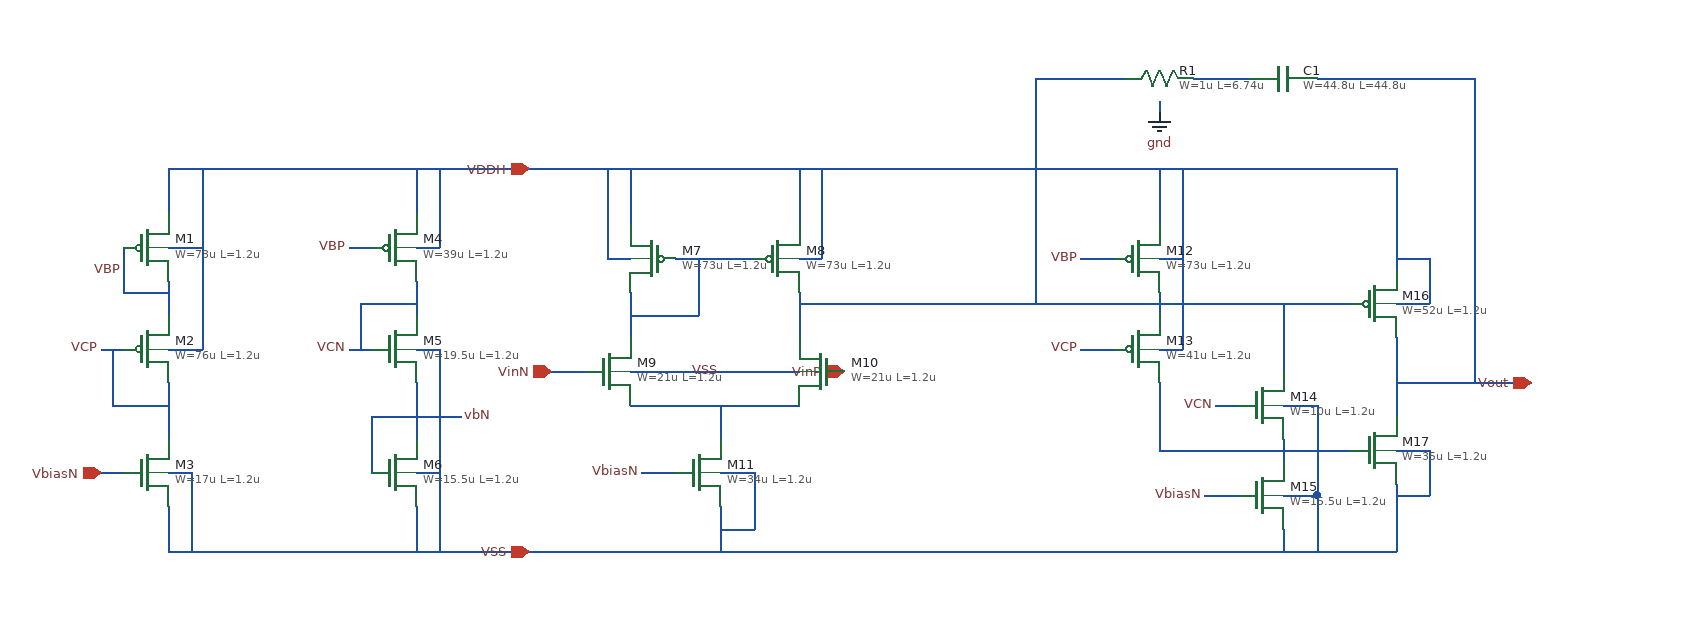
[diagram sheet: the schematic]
v {xschem version=3.4.8RC file_version=1.3}
G {}
K {}
V {}
S {}
F {}
E {}
N -3610 -1060 -3610 -1030 {lab=VBP}
N -3610 -970 -3610 -920 {lab=VCP}
N -3650 -1090 -3650 -1050 {lab=VBP}
N -3650 -1050 -3610 -1050 {lab=VBP}
N -3670 -1000 -3650 -1000 {lab=VCP}
N -3660 -1000 -3660 -950 {lab=VCP}
N -3660 -950 -3610 -950 {lab=VCP}
N -3610 -860 -3610 -820 {lab=VSS}
N -3610 -820 -2930 -820 {lab=VSS}
N -3610 -890 -3590 -890 {lab=VSS}
N -3590 -890 -3590 -820 {lab=VSS}
N -3670 -890 -3650 -890 {lab=VbiasN}
N -3610 -1000 -3580 -1000 {lab=VDDH}
N -3580 -1160 -3580 -1000 {lab=VDDH}
N -3610 -1090 -3580 -1090 {lab=VDDH}
N -3610 -1160 -3610 -1120 {lab=VDDH}
N -3610 -1160 -2940 -1160 {lab=VDDH}
N -3390 -1160 -3390 -1120 {lab=VDDH}
N -3390 -1090 -3370 -1090 {lab=VDDH}
N -3370 -1160 -3370 -1090 {lab=VDDH}
N -3450 -1090 -3430 -1090 {lab=VBP}
N -3390 -1060 -3390 -1030 {lab=VCN}
N -3390 -970 -3390 -920 {lab=vbN}
N -3390 -860 -3390 -820 {lab=VSS}
N -3390 -890 -3370 -890 {lab=VSS}
N -3370 -890 -3370 -820 {lab=VSS}
N -3390 -1000 -3370 -1000 {lab=VSS}
N -3370 -1000 -3370 -880 {lab=VSS}
N -3450 -1000 -3430 -1000 {lab=VCN}
N -3440 -1040 -3440 -1000 {lab=VCN}
N -3440 -1040 -3390 -1040 {lab=VCN}
N -3430 -940 -3430 -890 {lab=vbN}
N -3430 -940 -3390 -940 {lab=vbN}
N -3390 -940 -3350 -940 {lab=vbN}
N -3200 -1160 -3200 -1110 {lab=VDDH}
N -3220 -1080 -3200 -1080 {lab=VDDH}
N -3220 -1160 -3220 -1080 {lab=VDDH}
N -3200 -1050 -3200 -1010 {lab=#net1}
N -3200 -1030 -3200 -1010 {lab=#net1}
N -3200 -1030 -3140 -1030 {lab=#net1}
N -3140 -1080 -3140 -1030 {lab=#net1}
N -3200 -950 -3050 -950 {lab=#net2}
N -3120 -950 -3120 -920 {lab=#net2}
N -3200 -980 -3050 -980 {lab=VSS}
N -3270 -980 -3240 -980 {lab=VinN}
N -3120 -890 -3090 -890 {lab=VSS}
N -3090 -890 -3090 -840 {lab=VSS}
N -3120 -840 -3090 -840 {lab=VSS}
N -3120 -860 -3120 -820 {lab=VSS}
N -3190 -890 -3160 -890 {lab=VbiasN}
N -2800 -1080 -2770 -1080 {lab=VBP}
N -2800 -1000 -2770 -1000 {lab=VCP}
N -2730 -1050 -2730 -1030 {lab=#net3}
N -2940 -1160 -2530 -1160 {lab=VDDH}
N -2730 -1160 -2730 -1110 {lab=VDDH}
N -2730 -1080 -2710 -1080 {lab=VDDH}
N -2710 -1160 -2710 -1080 {lab=VDDH}
N -2730 -1000 -2710 -1000 {lab=VDDH}
N -2710 -1100 -2710 -1000 {lab=VDDH}
N -2620 -920 -2620 -900 {lab=#net4}
N -2690 -870 -2660 -870 {lab=VbiasN}
N -2620 -840 -2620 -820 {lab=VSS}
N -2620 -870 -2590 -870 {lab=VSS}
N -2590 -870 -2590 -820 {lab=VSS}
N -2620 -950 -2590 -950 {lab=VSS}
N -2590 -950 -2590 -870 {lab=VSS}
N -2680 -950 -2660 -950 {lab=VCN}
N -2620 -1040 -2620 -980 {lab=#net3}
N -2730 -1040 -2560 -1040 {lab=#net3}
N -2520 -1010 -2520 -940 {lab=Vout}
N -2620 -910 -2560 -910 {lab=#net4}
N -2520 -880 -2520 -820 {lab=VSS}
N -2940 -820 -2520 -820 {lab=VSS}
N -2520 -910 -2490 -910 {lab=VSS}
N -2490 -910 -2490 -870 {lab=VSS}
N -2520 -870 -2490 -870 {lab=VSS}
N -2520 -1160 -2520 -1070 {lab=VDDH}
N -2530 -1160 -2520 -1160 {lab=VDDH}
N -2520 -1040 -2490 -1040 {lab=VDDH}
N -2490 -1080 -2490 -1040 {lab=VDDH}
N -2520 -1080 -2490 -1080 {lab=VDDH}
N -2520 -970 -2400 -970 {lab=Vout}
N -3050 -1160 -3050 -1110 {lab=VDDH}
N -3160 -1080 -3090 -1080 {lab=#net1}
N -3050 -1050 -3050 -1010 {lab=#net3}
N -2850 -1040 -2730 -1040 {lab=#net3}
N -3050 -1040 -2830 -1040 {lab=#net3}
N -2840 -1240 -2840 -1070 {lab=#net3}
N -2840 -1240 -2760 -1240 {lab=#net3}
N -2840 -1070 -2840 -1040 {lab=#net3}
N -2730 -1220 -2730 -1210 {lab=gnd}
N -2700 -1240 -2650 -1240 {lab=#net5}
N -2590 -1240 -2450 -1240 {lab=Vout}
N -2450 -1240 -2450 -970 {lab=Vout}
N -3050 -1080 -3030 -1080 {lab=VDDH}
N -3030 -1160 -3030 -1080 {lab=VDDH}
N -2730 -970 -2730 -910 {lab=#net4}
N -2730 -910 -2620 -910 {lab=#net4}
C {symbols/ppolyf_u.sym} -2730 -1240 3 0 {name=R1
W=1u
L=6.74u
model=ppolyf_u
spiceprefix=X
m=1}
C {symbols/cap_mim_2f0fF.sym} -2620 -1240 3 0 {name=C1
W=44.8u
L=44.8u
model=cap_mim_2f0fF
spiceprefix=X
m=1}
C {gnd.sym} -2730 -1210 0 0 {name=l1 lab=gnd}
C {ipin.sym} -3670 -890 0 0 {name=p1 lab=VbiasN}
C {ipin.sym} -3290 -820 3 0 {name=p2 lab=VSS}
C {ipin.sym} -3290 -1160 1 0 {name=p3 lab=VDDH}
C {ipin.sym} -3270 -980 0 0 {name=p4 lab=VinN}
C {ipin.sym} -3010 -980 2 0 {name=p5 lab=VinP}
C {ipin.sym} -2400 -970 2 0 {name=p6 lab=Vout}
C {lab_pin.sym} -3450 -1090 0 0 {name=p7 sig_type=std_logic lab=VBP}
C {lab_pin.sym} -3450 -1000 0 0 {name=p8 sig_type=std_logic lab=VCN}
C {lab_pin.sym} -3350 -940 2 0 {name=p9 sig_type=std_logic lab=vbN}
C {lab_pin.sym} -3670 -1000 0 0 {name=p10 sig_type=std_logic lab=VCP}
C {lab_pin.sym} -3650 -1070 0 0 {name=p11 sig_type=std_logic lab=VBP}
C {lab_pin.sym} -3190 -890 0 0 {name=p12 sig_type=std_logic lab=VbiasN}
C {lab_pin.sym} -2690 -870 0 0 {name=p13 sig_type=std_logic lab=VbiasN}
C {lab_pin.sym} -2680 -950 0 0 {name=p14 sig_type=std_logic lab=VCN}
C {lab_pin.sym} -2800 -1000 0 0 {name=p15 sig_type=std_logic lab=VCP}
C {lab_pin.sym} -2800 -1080 0 0 {name=p16 sig_type=std_logic lab=VBP}
C {lab_pin.sym} -3120 -980 0 0 {name=p17 sig_type=std_logic lab=VSS}
C {symbols/nfet_03v3.sym} -3140 -890 0 0 {name=M11
L=1.2u
W=34u
nf=8
m=1
ad="'int((nf+1)/2) * W/nf * 0.18u'"
pd="'2*int((nf+1)/2) * (W/nf + 0.18u)'"
as="'int((nf+2)/2) * W/nf * 0.18u'"
ps="'2*int((nf+2)/2) * (W/nf + 0.18u)'"
nrd="'0.18u / W'" nrs="'0.18u / W'"
sa=0 sb=0 sd=0
model=nfet_03v3
spiceprefix=X
}
C {symbols/pfet_03v3.sym} -3180 -1080 0 1 {name=M7
L=1.2u
W=73u
nf=16
m=1
ad="'int((nf+1)/2) * W/nf * 0.18u'"
pd="'2*int((nf+1)/2) * (W/nf + 0.18u)'"
as="'int((nf+2)/2) * W/nf * 0.18u'"
ps="'2*int((nf+2)/2) * (W/nf + 0.18u)'"
nrd="'0.18u / W'" nrs="'0.18u / W'"
sa=0 sb=0 sd=0
model=pfet_03v3
spiceprefix=X
}
C {symbols/pfet_03v3.sym} -3070 -1080 0 0 {name=M8
L=1.2u
W=73u
nf=16
m=1
ad="'int((nf+1)/2) * W/nf * 0.18u'"
pd="'2*int((nf+1)/2) * (W/nf + 0.18u)'"
as="'int((nf+2)/2) * W/nf * 0.18u'"
ps="'2*int((nf+2)/2) * (W/nf + 0.18u)'"
nrd="'0.18u / W'" nrs="'0.18u / W'"
sa=0 sb=0 sd=0
model=pfet_03v3
spiceprefix=X
}
C {symbols/nfet_03v3.sym} -3220 -980 0 0 {name=M9
L=1.2u
W=21u
nf=5
m=1
ad="'int((nf+1)/2) * W/nf * 0.18u'"
pd="'2*int((nf+1)/2) * (W/nf + 0.18u)'"
as="'int((nf+2)/2) * W/nf * 0.18u'"
ps="'2*int((nf+2)/2) * (W/nf + 0.18u)'"
nrd="'0.18u / W'" nrs="'0.18u / W'"
sa=0 sb=0 sd=0
model=nfet_03v3
spiceprefix=X
}
C {symbols/nfet_03v3.sym} -3030 -980 0 1 {name=M10
L=1.2u
W=21u
nf=5
m=1
ad="'int((nf+1)/2) * W/nf * 0.18u'"
pd="'2*int((nf+1)/2) * (W/nf + 0.18u)'"
as="'int((nf+2)/2) * W/nf * 0.18u'"
ps="'2*int((nf+2)/2) * (W/nf + 0.18u)'"
nrd="'0.18u / W'" nrs="'0.18u / W'"
sa=0 sb=0 sd=0
model=nfet_03v3
spiceprefix=X
}
C {symbols/pfet_03v3.sym} -2750 -1080 0 0 {name=M12
L=1.2u
W=73u
nf=16
m=1
ad="'int((nf+1)/2) * W/nf * 0.18u'"
pd="'2*int((nf+1)/2) * (W/nf + 0.18u)'"
as="'int((nf+2)/2) * W/nf * 0.18u'"
ps="'2*int((nf+2)/2) * (W/nf + 0.18u)'"
nrd="'0.18u / W'" nrs="'0.18u / W'"
sa=0 sb=0 sd=0
model=pfet_03v3
spiceprefix=X
}
C {symbols/pfet_03v3.sym} -2750 -1000 0 0 {name=M13
L=1.2u
W=41u
nf=8
m=1
ad="'int((nf+1)/2) * W/nf * 0.18u'"
pd="'2*int((nf+1)/2) * (W/nf + 0.18u)'"
as="'int((nf+2)/2) * W/nf * 0.18u'"
ps="'2*int((nf+2)/2) * (W/nf + 0.18u)'"
nrd="'0.18u / W'" nrs="'0.18u / W'"
sa=0 sb=0 sd=0
model=pfet_03v3
spiceprefix=X
}
C {symbols/nfet_03v3.sym} -2640 -950 0 0 {name=M14
L=1.2u
W=10u
nf=4
m=1
ad="'int((nf+1)/2) * W/nf * 0.18u'"
pd="'2*int((nf+1)/2) * (W/nf + 0.18u)'"
as="'int((nf+2)/2) * W/nf * 0.18u'"
ps="'2*int((nf+2)/2) * (W/nf + 0.18u)'"
nrd="'0.18u / W'" nrs="'0.18u / W'"
sa=0 sb=0 sd=0
model=nfet_03v3
spiceprefix=X
}
C {symbols/nfet_03v3.sym} -2640 -870 0 0 {name=M15
L=1.2u
W=15.5u
nf=4
m=1
ad="'int((nf+1)/2) * W/nf * 0.18u'"
pd="'2*int((nf+1)/2) * (W/nf + 0.18u)'"
as="'int((nf+2)/2) * W/nf * 0.18u'"
ps="'2*int((nf+2)/2) * (W/nf + 0.18u)'"
nrd="'0.18u / W'" nrs="'0.18u / W'"
sa=0 sb=0 sd=0
model=nfet_03v3
spiceprefix=X
}
C {symbols/pfet_03v3.sym} -2540 -1040 0 0 {name=M16
L=1.2u
W=52u
nf=16
m=3
ad="'int((nf+1)/2) * W/nf * 0.18u'"
pd="'2*int((nf+1)/2) * (W/nf + 0.18u)'"
as="'int((nf+2)/2) * W/nf * 0.18u'"
ps="'2*int((nf+2)/2) * (W/nf + 0.18u)'"
nrd="'0.18u / W'" nrs="'0.18u / W'"
sa=0 sb=0 sd=0
model=pfet_03v3
spiceprefix=X
}
C {symbols/nfet_03v3.sym} -2540 -910 0 0 {name=M17
L=1.2u
W=35u
nf=8
m=1
ad="'int((nf+1)/2) * W/nf * 0.18u'"
pd="'2*int((nf+1)/2) * (W/nf + 0.18u)'"
as="'int((nf+2)/2) * W/nf * 0.18u'"
ps="'2*int((nf+2)/2) * (W/nf + 0.18u)'"
nrd="'0.18u / W'" nrs="'0.18u / W'"
sa=0 sb=0 sd=0
model=nfet_03v3
spiceprefix=X
}
C {symbols/pfet_03v3.sym} -3630 -1090 0 0 {name=M1
L=1.2u
W=73u
nf=16
m=1
ad="'int((nf+1)/2) * W/nf * 0.18u'"
pd="'2*int((nf+1)/2) * (W/nf + 0.18u)'"
as="'int((nf+2)/2) * W/nf * 0.18u'"
ps="'2*int((nf+2)/2) * (W/nf + 0.18u)'"
nrd="'0.18u / W'" nrs="'0.18u / W'"
sa=0 sb=0 sd=0
model=pfet_03v3
spiceprefix=X
}
C {symbols/pfet_03v3.sym} -3630 -1000 0 0 {name=M2
L=1.2u
W=76u
nf=16
m=1
ad="'int((nf+1)/2) * W/nf * 0.18u'"
pd="'2*int((nf+1)/2) * (W/nf + 0.18u)'"
as="'int((nf+2)/2) * W/nf * 0.18u'"
ps="'2*int((nf+2)/2) * (W/nf + 0.18u)'"
nrd="'0.18u / W'" nrs="'0.18u / W'"
sa=0 sb=0 sd=0
model=pfet_03v3
spiceprefix=X
}
C {symbols/nfet_03v3.sym} -3630 -890 0 0 {name=M3
L=1.2u
W=17u
nf=4
m=1
ad="'int((nf+1)/2) * W/nf * 0.18u'"
pd="'2*int((nf+1)/2) * (W/nf + 0.18u)'"
as="'int((nf+2)/2) * W/nf * 0.18u'"
ps="'2*int((nf+2)/2) * (W/nf + 0.18u)'"
nrd="'0.18u / W'" nrs="'0.18u / W'"
sa=0 sb=0 sd=0
model=nfet_03v3
spiceprefix=X
}
C {symbols/pfet_03v3.sym} -3410 -1090 0 0 {name=M4
L=1.2u
W=39u
nf=16
m=2
ad="'int((nf+1)/2) * W/nf * 0.18u'"
pd="'2*int((nf+1)/2) * (W/nf + 0.18u)'"
as="'int((nf+2)/2) * W/nf * 0.18u'"
ps="'2*int((nf+2)/2) * (W/nf + 0.18u)'"
nrd="'0.18u / W'" nrs="'0.18u / W'"
sa=0 sb=0 sd=0
model=pfet_03v3
spiceprefix=X
}
C {symbols/nfet_03v3.sym} -3410 -1000 0 0 {name=M5
L=1.2u
W=19.5u
nf=4
m=1
ad="'int((nf+1)/2) * W/nf * 0.18u'"
pd="'2*int((nf+1)/2) * (W/nf + 0.18u)'"
as="'int((nf+2)/2) * W/nf * 0.18u'"
ps="'2*int((nf+2)/2) * (W/nf + 0.18u)'"
nrd="'0.18u / W'" nrs="'0.18u / W'"
sa=0 sb=0 sd=0
model=nfet_03v3
spiceprefix=X
}
C {symbols/nfet_03v3.sym} -3410 -890 0 0 {name=M6
L=1.2u
W=15.5u
nf=4
m=1
ad="'int((nf+1)/2) * W/nf * 0.18u'"
pd="'2*int((nf+1)/2) * (W/nf + 0.18u)'"
as="'int((nf+2)/2) * W/nf * 0.18u'"
ps="'2*int((nf+2)/2) * (W/nf + 0.18u)'"
nrd="'0.18u / W'" nrs="'0.18u / W'"
sa=0 sb=0 sd=0
model=nfet_03v3
spiceprefix=X
}

